VERSION 5.7 ;
  NAMESCASESENSITIVE ON ;
  NOWIREEXTENSIONATPIN ON ;
  DIVIDERCHAR "/" ;
  BUSBITCHARS "[]" ;
UNITS
  DATABASE MICRONS 200 ;
END UNITS

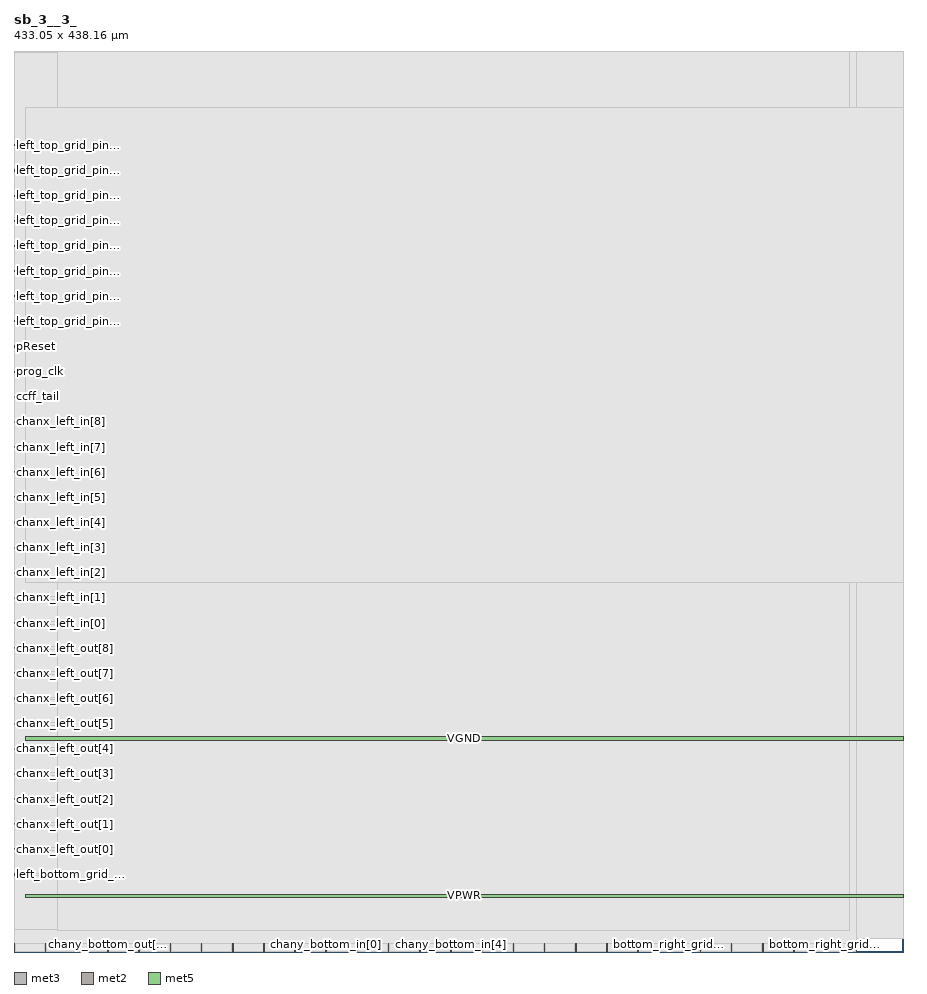
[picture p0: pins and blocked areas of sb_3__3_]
MACRO sb_3__3_
  CLASS BLOCK ;
  FOREIGN sb_3__3_ ;
  ORIGIN 0.000 0.000 ;
  SIZE 433.050 BY 438.160 ;
  PIN left_bottom_grid_pin_12_
    DIRECTION INPUT ;
    PORT
      LAYER met3 ;
        RECT 0.000 37.440 4.000 38.040 ;
    END
  END left_bottom_grid_pin_12_
  PIN chanx_left_out[0]
    DIRECTION OUTPUT TRISTATE ;
    PORT
      LAYER met3 ;
        RECT 0.000 49.680 4.000 50.280 ;
    END
  END chanx_left_out[0]
  PIN chanx_left_out[1]
    DIRECTION OUTPUT TRISTATE ;
    PORT
      LAYER met3 ;
        RECT 0.000 61.920 4.000 62.520 ;
    END
  END chanx_left_out[1]
  PIN chanx_left_out[2]
    DIRECTION OUTPUT TRISTATE ;
    PORT
      LAYER met3 ;
        RECT 0.000 74.160 4.000 74.760 ;
    END
  END chanx_left_out[2]
  PIN chanx_left_out[3]
    DIRECTION OUTPUT TRISTATE ;
    PORT
      LAYER met3 ;
        RECT 0.000 86.400 4.000 87.000 ;
    END
  END chanx_left_out[3]
  PIN chanx_left_out[4]
    DIRECTION OUTPUT TRISTATE ;
    PORT
      LAYER met3 ;
        RECT 0.000 98.640 4.000 99.240 ;
    END
  END chanx_left_out[4]
  PIN chanx_left_out[5]
    DIRECTION OUTPUT TRISTATE ;
    PORT
      LAYER met3 ;
        RECT 0.000 110.880 4.000 111.480 ;
    END
  END chanx_left_out[5]
  PIN chanx_left_out[6]
    DIRECTION OUTPUT TRISTATE ;
    PORT
      LAYER met3 ;
        RECT 0.000 123.120 4.000 123.720 ;
    END
  END chanx_left_out[6]
  PIN chanx_left_out[7]
    DIRECTION OUTPUT TRISTATE ;
    PORT
      LAYER met3 ;
        RECT 0.000 135.360 4.000 135.960 ;
    END
  END chanx_left_out[7]
  PIN chanx_left_out[8]
    DIRECTION OUTPUT TRISTATE ;
    PORT
      LAYER met3 ;
        RECT 0.000 147.600 4.000 148.200 ;
    END
  END chanx_left_out[8]
  PIN chanx_left_in[0]
    DIRECTION INPUT ;
    PORT
      LAYER met3 ;
        RECT 0.000 159.840 4.000 160.440 ;
    END
  END chanx_left_in[0]
  PIN chanx_left_in[1]
    DIRECTION INPUT ;
    PORT
      LAYER met3 ;
        RECT 0.000 172.080 4.000 172.680 ;
    END
  END chanx_left_in[1]
  PIN chanx_left_in[2]
    DIRECTION INPUT ;
    PORT
      LAYER met3 ;
        RECT 0.000 184.320 4.000 184.920 ;
    END
  END chanx_left_in[2]
  PIN chanx_left_in[3]
    DIRECTION INPUT ;
    PORT
      LAYER met3 ;
        RECT 0.000 196.560 4.000 197.160 ;
    END
  END chanx_left_in[3]
  PIN chanx_left_in[4]
    DIRECTION INPUT ;
    PORT
      LAYER met3 ;
        RECT 0.000 208.800 4.000 209.400 ;
    END
  END chanx_left_in[4]
  PIN chanx_left_in[5]
    DIRECTION INPUT ;
    PORT
      LAYER met3 ;
        RECT 0.000 221.040 4.000 221.640 ;
    END
  END chanx_left_in[5]
  PIN chanx_left_in[6]
    DIRECTION INPUT ;
    PORT
      LAYER met3 ;
        RECT 0.000 233.280 4.000 233.880 ;
    END
  END chanx_left_in[6]
  PIN chanx_left_in[7]
    DIRECTION INPUT ;
    PORT
      LAYER met3 ;
        RECT 0.000 245.520 4.000 246.120 ;
    END
  END chanx_left_in[7]
  PIN chanx_left_in[8]
    DIRECTION INPUT ;
    PORT
      LAYER met3 ;
        RECT 0.000 257.760 4.000 258.360 ;
    END
  END chanx_left_in[8]
  PIN ccff_tail
    DIRECTION OUTPUT TRISTATE ;
    PORT
      LAYER met3 ;
        RECT 0.000 270.000 4.000 270.600 ;
    END
  END ccff_tail
  PIN prog_clk
    DIRECTION INPUT ;
    PORT
      LAYER met3 ;
        RECT 0.000 282.240 4.000 282.840 ;
    END
  END prog_clk
  PIN pReset
    DIRECTION INPUT ;
    PORT
      LAYER met3 ;
        RECT 0.000 294.480 4.000 295.080 ;
    END
  END pReset
  PIN left_top_grid_pin_15_
    DIRECTION INPUT ;
    PORT
      LAYER met3 ;
        RECT 0.000 306.720 4.000 307.320 ;
    END
  END left_top_grid_pin_15_
  PIN left_top_grid_pin_13_
    DIRECTION INPUT ;
    PORT
      LAYER met3 ;
        RECT 0.000 318.960 4.000 319.560 ;
    END
  END left_top_grid_pin_13_
  PIN left_top_grid_pin_11_
    DIRECTION INPUT ;
    PORT
      LAYER met3 ;
        RECT 0.000 331.200 4.000 331.800 ;
    END
  END left_top_grid_pin_11_
  PIN left_top_grid_pin_9_
    DIRECTION INPUT ;
    PORT
      LAYER met3 ;
        RECT 0.000 343.440 4.000 344.040 ;
    END
  END left_top_grid_pin_9_
  PIN left_top_grid_pin_7_
    DIRECTION INPUT ;
    PORT
      LAYER met3 ;
        RECT 0.000 355.680 4.000 356.280 ;
    END
  END left_top_grid_pin_7_
  PIN left_top_grid_pin_5_
    DIRECTION INPUT ;
    PORT
      LAYER met3 ;
        RECT 0.000 367.920 4.000 368.520 ;
    END
  END left_top_grid_pin_5_
  PIN left_top_grid_pin_3_
    DIRECTION INPUT ;
    PORT
      LAYER met3 ;
        RECT 0.000 380.160 4.000 380.760 ;
    END
  END left_top_grid_pin_3_
  PIN left_top_grid_pin_1_
    DIRECTION INPUT ;
    PORT
      LAYER met3 ;
        RECT 0.000 392.400 4.000 393.000 ;
    END
  END left_top_grid_pin_1_
  PIN bottom_left_grid_pin_13_
    DIRECTION INPUT ;
    PORT
      LAYER met2 ;
        RECT 0.090 0.000 0.370 4.000 ;
    END
  END bottom_left_grid_pin_13_
  PIN chany_bottom_out[0]
    DIRECTION OUTPUT TRISTATE ;
    PORT
      LAYER met2 ;
        RECT 15.270 0.000 15.550 4.000 ;
    END
  END chany_bottom_out[0]
  PIN chany_bottom_out[1]
    DIRECTION OUTPUT TRISTATE ;
    PORT
      LAYER met2 ;
        RECT 30.450 0.000 30.730 4.000 ;
    END
  END chany_bottom_out[1]
  PIN chany_bottom_out[2]
    DIRECTION OUTPUT TRISTATE ;
    PORT
      LAYER met2 ;
        RECT 45.630 0.000 45.910 4.000 ;
    END
  END chany_bottom_out[2]
  PIN chany_bottom_out[3]
    DIRECTION OUTPUT TRISTATE ;
    PORT
      LAYER met2 ;
        RECT 60.810 0.000 61.090 4.000 ;
    END
  END chany_bottom_out[3]
  PIN chany_bottom_out[4]
    DIRECTION OUTPUT TRISTATE ;
    PORT
      LAYER met2 ;
        RECT 75.990 0.000 76.270 4.000 ;
    END
  END chany_bottom_out[4]
  PIN chany_bottom_out[5]
    DIRECTION OUTPUT TRISTATE ;
    PORT
      LAYER met2 ;
        RECT 91.170 0.000 91.450 4.000 ;
    END
  END chany_bottom_out[5]
  PIN chany_bottom_out[6]
    DIRECTION OUTPUT TRISTATE ;
    PORT
      LAYER met2 ;
        RECT 106.350 0.000 106.630 4.000 ;
    END
  END chany_bottom_out[6]
  PIN chany_bottom_out[7]
    DIRECTION OUTPUT TRISTATE ;
    PORT
      LAYER met2 ;
        RECT 121.530 0.000 121.810 4.000 ;
    END
  END chany_bottom_out[7]
  PIN chany_bottom_out[8]
    DIRECTION OUTPUT TRISTATE ;
    PORT
      LAYER met2 ;
        RECT 136.710 0.000 136.990 4.000 ;
    END
  END chany_bottom_out[8]
  PIN chany_bottom_in[0]
    DIRECTION INPUT ;
    PORT
      LAYER met2 ;
        RECT 151.890 0.000 152.170 4.000 ;
    END
  END chany_bottom_in[0]
  PIN chany_bottom_in[1]
    DIRECTION INPUT ;
    PORT
      LAYER met2 ;
        RECT 167.070 0.000 167.350 4.000 ;
    END
  END chany_bottom_in[1]
  PIN chany_bottom_in[2]
    DIRECTION INPUT ;
    PORT
      LAYER met2 ;
        RECT 182.250 0.000 182.530 4.000 ;
    END
  END chany_bottom_in[2]
  PIN chany_bottom_in[3]
    DIRECTION INPUT ;
    PORT
      LAYER met2 ;
        RECT 197.430 0.000 197.710 4.000 ;
    END
  END chany_bottom_in[3]
  PIN chany_bottom_in[4]
    DIRECTION INPUT ;
    PORT
      LAYER met2 ;
        RECT 212.610 0.000 212.890 4.000 ;
    END
  END chany_bottom_in[4]
  PIN chany_bottom_in[5]
    DIRECTION INPUT ;
    PORT
      LAYER met2 ;
        RECT 227.790 0.000 228.070 4.000 ;
    END
  END chany_bottom_in[5]
  PIN chany_bottom_in[6]
    DIRECTION INPUT ;
    PORT
      LAYER met2 ;
        RECT 242.970 0.000 243.250 4.000 ;
    END
  END chany_bottom_in[6]
  PIN chany_bottom_in[7]
    DIRECTION INPUT ;
    PORT
      LAYER met2 ;
        RECT 258.150 0.000 258.430 4.000 ;
    END
  END chany_bottom_in[7]
  PIN chany_bottom_in[8]
    DIRECTION INPUT ;
    PORT
      LAYER met2 ;
        RECT 273.330 0.000 273.610 4.000 ;
    END
  END chany_bottom_in[8]
  PIN bottom_right_grid_pin_15_
    DIRECTION INPUT ;
    PORT
      LAYER met2 ;
        RECT 288.510 0.000 288.790 4.000 ;
    END
  END bottom_right_grid_pin_15_
  PIN bottom_right_grid_pin_13_
    DIRECTION INPUT ;
    PORT
      LAYER met2 ;
        RECT 303.690 0.000 303.970 4.000 ;
    END
  END bottom_right_grid_pin_13_
  PIN bottom_right_grid_pin_11_
    DIRECTION INPUT ;
    PORT
      LAYER met2 ;
        RECT 318.870 0.000 319.150 4.000 ;
    END
  END bottom_right_grid_pin_11_
  PIN bottom_right_grid_pin_9_
    DIRECTION INPUT ;
    PORT
      LAYER met2 ;
        RECT 334.050 0.000 334.330 4.000 ;
    END
  END bottom_right_grid_pin_9_
  PIN bottom_right_grid_pin_7_
    DIRECTION INPUT ;
    PORT
      LAYER met2 ;
        RECT 349.230 0.000 349.510 4.000 ;
    END
  END bottom_right_grid_pin_7_
  PIN bottom_right_grid_pin_5_
    DIRECTION INPUT ;
    PORT
      LAYER met2 ;
        RECT 364.410 0.000 364.690 4.000 ;
    END
  END bottom_right_grid_pin_5_
  PIN bottom_right_grid_pin_3_
    DIRECTION INPUT ;
    PORT
      LAYER met2 ;
        RECT 379.590 0.000 379.870 4.000 ;
    END
  END bottom_right_grid_pin_3_
  PIN bottom_right_grid_pin_1_
    DIRECTION INPUT ;
    PORT
      LAYER met2 ;
        RECT 394.770 0.000 395.050 4.000 ;
    END
  END bottom_right_grid_pin_1_
  PIN ccff_head
    DIRECTION INPUT ;
    PORT
      LAYER met2 ;
        RECT 409.950 0.000 410.230 4.000 ;
    END
  END ccff_head
  PIN VPWR
    DIRECTION INPUT ;
    USE POWER ;
    PORT
      LAYER met5 ;
        RECT 5.520 26.490 432.860 28.090 ;
    END
  END VPWR
  PIN VGND
    DIRECTION INPUT ;
    USE GROUND ;
    PORT
      LAYER met5 ;
        RECT 5.520 103.080 432.860 104.680 ;
    END
  END VGND
  OBS
      LAYER li1 ;
        RECT 5.520 10.795 432.860 438.005 ;
      LAYER met1 ;
        RECT 0.530 6.500 432.860 438.160 ;
      LAYER met2 ;
        RECT 0.090 4.280 409.950 438.160 ;
        RECT 0.650 0.270 14.990 4.280 ;
        RECT 15.830 0.270 30.170 4.280 ;
        RECT 31.010 0.270 45.350 4.280 ;
        RECT 46.190 0.270 60.530 4.280 ;
        RECT 61.370 0.270 75.710 4.280 ;
        RECT 76.550 0.270 90.890 4.280 ;
        RECT 91.730 0.270 106.070 4.280 ;
        RECT 106.910 0.270 121.250 4.280 ;
        RECT 122.090 0.270 136.430 4.280 ;
        RECT 137.270 0.270 151.610 4.280 ;
        RECT 152.450 0.270 166.790 4.280 ;
        RECT 167.630 0.270 181.970 4.280 ;
        RECT 182.810 0.270 197.150 4.280 ;
        RECT 197.990 0.270 212.330 4.280 ;
        RECT 213.170 0.270 227.510 4.280 ;
        RECT 228.350 0.270 242.690 4.280 ;
        RECT 243.530 0.270 257.870 4.280 ;
        RECT 258.710 0.270 273.050 4.280 ;
        RECT 273.890 0.270 288.230 4.280 ;
        RECT 289.070 0.270 303.410 4.280 ;
        RECT 304.250 0.270 318.590 4.280 ;
        RECT 319.430 0.270 333.770 4.280 ;
        RECT 334.610 0.270 348.950 4.280 ;
        RECT 349.790 0.270 364.130 4.280 ;
        RECT 364.970 0.270 379.310 4.280 ;
        RECT 380.150 0.270 394.490 4.280 ;
        RECT 395.330 0.270 409.670 4.280 ;
      LAYER met3 ;
        RECT 0.310 393.400 406.640 438.085 ;
        RECT 4.400 392.000 406.640 393.400 ;
        RECT 0.310 381.160 406.640 392.000 ;
        RECT 4.400 379.760 406.640 381.160 ;
        RECT 0.310 368.920 406.640 379.760 ;
        RECT 4.400 367.520 406.640 368.920 ;
        RECT 0.310 356.680 406.640 367.520 ;
        RECT 4.400 355.280 406.640 356.680 ;
        RECT 0.310 344.440 406.640 355.280 ;
        RECT 4.400 343.040 406.640 344.440 ;
        RECT 0.310 332.200 406.640 343.040 ;
        RECT 4.400 330.800 406.640 332.200 ;
        RECT 0.310 319.960 406.640 330.800 ;
        RECT 4.400 318.560 406.640 319.960 ;
        RECT 0.310 307.720 406.640 318.560 ;
        RECT 4.400 306.320 406.640 307.720 ;
        RECT 0.310 295.480 406.640 306.320 ;
        RECT 4.400 294.080 406.640 295.480 ;
        RECT 0.310 283.240 406.640 294.080 ;
        RECT 4.400 281.840 406.640 283.240 ;
        RECT 0.310 271.000 406.640 281.840 ;
        RECT 4.400 269.600 406.640 271.000 ;
        RECT 0.310 258.760 406.640 269.600 ;
        RECT 4.400 257.360 406.640 258.760 ;
        RECT 0.310 246.520 406.640 257.360 ;
        RECT 4.400 245.120 406.640 246.520 ;
        RECT 0.310 234.280 406.640 245.120 ;
        RECT 4.400 232.880 406.640 234.280 ;
        RECT 0.310 222.040 406.640 232.880 ;
        RECT 4.400 220.640 406.640 222.040 ;
        RECT 0.310 209.800 406.640 220.640 ;
        RECT 4.400 208.400 406.640 209.800 ;
        RECT 0.310 197.560 406.640 208.400 ;
        RECT 4.400 196.160 406.640 197.560 ;
        RECT 0.310 185.320 406.640 196.160 ;
        RECT 4.400 183.920 406.640 185.320 ;
        RECT 0.310 173.080 406.640 183.920 ;
        RECT 4.400 171.680 406.640 173.080 ;
        RECT 0.310 160.840 406.640 171.680 ;
        RECT 4.400 159.440 406.640 160.840 ;
        RECT 0.310 148.600 406.640 159.440 ;
        RECT 4.400 147.200 406.640 148.600 ;
        RECT 0.310 136.360 406.640 147.200 ;
        RECT 4.400 134.960 406.640 136.360 ;
        RECT 0.310 124.120 406.640 134.960 ;
        RECT 4.400 122.720 406.640 124.120 ;
        RECT 0.310 111.880 406.640 122.720 ;
        RECT 4.400 110.480 406.640 111.880 ;
        RECT 0.310 99.640 406.640 110.480 ;
        RECT 4.400 98.240 406.640 99.640 ;
        RECT 0.310 87.400 406.640 98.240 ;
        RECT 4.400 86.000 406.640 87.400 ;
        RECT 0.310 75.160 406.640 86.000 ;
        RECT 4.400 73.760 406.640 75.160 ;
        RECT 0.310 62.920 406.640 73.760 ;
        RECT 4.400 61.520 406.640 62.920 ;
        RECT 0.310 50.680 406.640 61.520 ;
        RECT 4.400 49.280 406.640 50.680 ;
        RECT 0.310 38.440 406.640 49.280 ;
        RECT 4.400 37.040 406.640 38.440 ;
        RECT 0.310 10.715 406.640 37.040 ;
      LAYER met4 ;
        RECT 21.040 10.640 406.640 438.160 ;
      LAYER met5 ;
        RECT 5.520 179.670 432.860 411.040 ;
  END
END sb_3__3_
END LIBRARY

